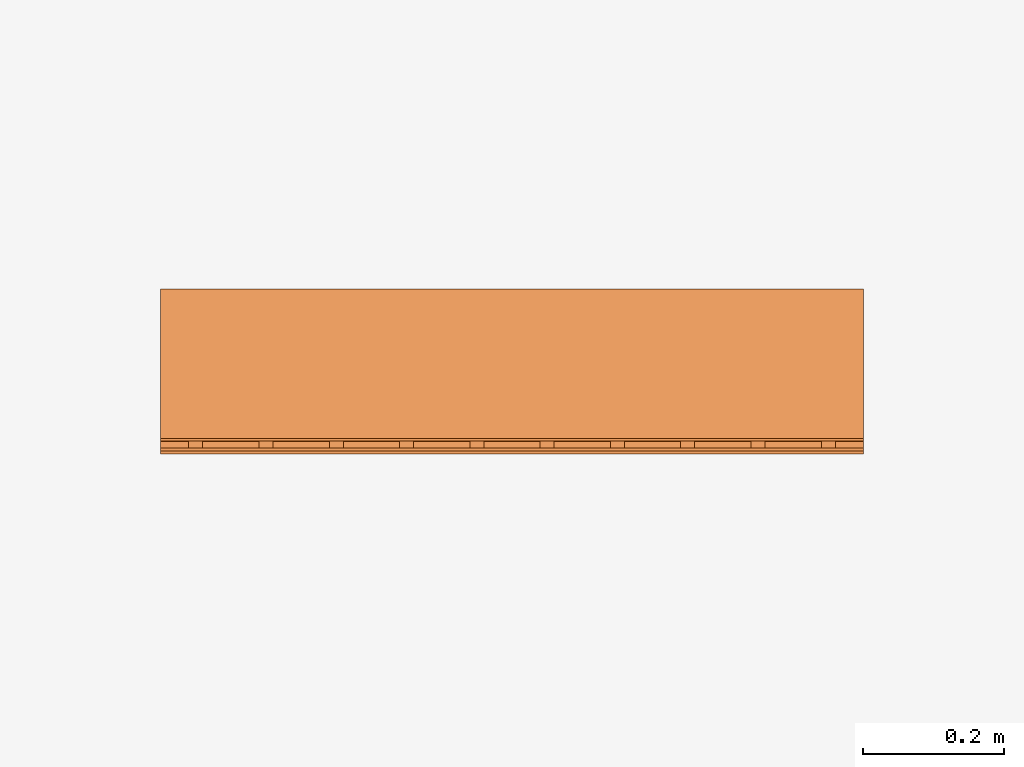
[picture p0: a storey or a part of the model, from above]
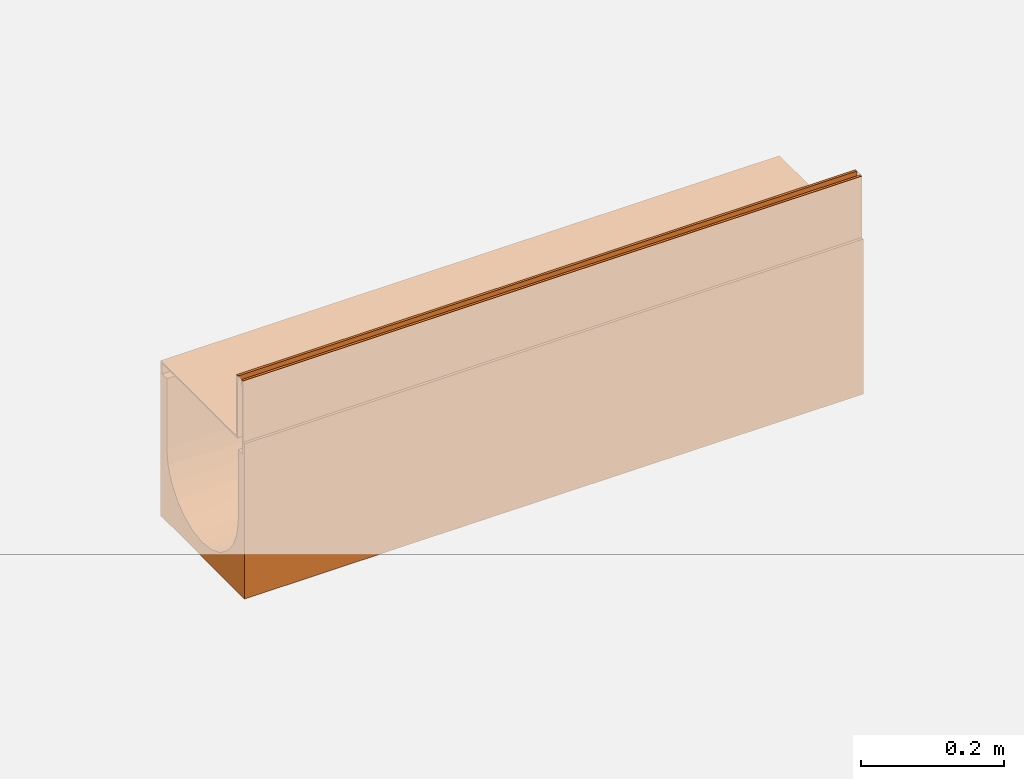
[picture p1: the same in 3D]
Properties of the parts of a building model (IFC2X3)

# File
Description: ViewDefinition [CoordinationView]
File name: 24210 - No 0.0 Constant Depth Channel - 1000mm LG - Invert Depth 240mm.ifc
Time: 2013-10-30T14:04:48
Written by: Autodesk Revit 2013
Made in: 20120221_2030(x64)

# IfcProject, Project Number
LongName: Project Name; Phase: Project Status

# IfcSite, Default
RefLatitude: 42, 21, 30, 344238; RefLongitude: -71, -3, -35, -194702; RefElevation: 0 mm

# IfcBuilding
Pset_BuildingCommon - NumberOfStoreys: 1
Other - Project Name: Project Name; Client Name: Owner; Project Status: Project Status; Project Number: Project Number; Project Address: ## Street City, State Zip; Project Issue Date: Issue Date

# IfcBuildingStorey, Level 1
LongName: Level 1; Elevation: 0 mm
Constraints - Elevation Base: 0; Elevation: 0 mm
Graphics - Line Pattern: Center; Symbol at End 1 Default: no; Symbol: M_Level Head - Circle: M_Level Head - Circle; Symbol at End 2 Default: yes; Line Weight: 1; Color: 0
Dimensions - Computation Height: 0 mm
Identity Data - Structural: no; Building Story: yes; Name: Level 1

# IfcBuildingElementProxy: 24210 - No 0.0 Constant Depth Channel - 1000mm LG - Invert Depth 240mm, Civil-Drainage-Channel-ACO-MultiDrain-M200DS-Brickslot-Channel-System:24210 - No 0.0 Constant Depth Channel - 1000mm LG - Invert Depth 240mm:24210 - No 0.0 Constant Depth Channel - 1000mm LG - Invert Depth 240mm:196059
In: Level 1
Material: Stainless Steel (F), Vienite® Synthetic Resin Concrete
Dimensions - FloorCut_Length: -1000 mm; Brickslot Access Unit Void Depth: 6000 mm; EndCap Position: 1000 mm; Volume: 19055290 mm3; Brickslot Access Unit Void Bottom Depth: 6105 mm; Brickslot Grating Void Depth: 0 mm; Length: 1000 mm; Brickslot Void Length: -1000 mm; Custom_Void_Length: 0 mm; InvDepth: 140 mm; FloorCut_Depth: 265 mm; FloorCut_Width: 235 mm; Length Drain: -1000 mm; EndCap_Height: 265 mm; FloorCut_HorPosition: 117.5 mm; Depth: 265 mm
Construction - 23219 - Universal Endcap (Male End): no; 408999_Load Class C250 & D400_Brickslot Grating_Stainless Steel_500mm Long: no; 409000_Load Class C250 & D400_Brickslot_Access Unit_Stainless Steel_500mm Long: no; 408998_Load Class C250 & D400_Brickslot Grating_Stainless Steel_1000mm Long: yes; 23219 - Universal Endcap (Female End): no; 23410_Sump Unit: no; Constant Depth Channel_1000: yes; Shallow Depth Channel with seal: no; Constant Depth Channel_500: no; Shallow Depth Channel: no
Constraints - Level: Level: Level 1; Moves With Nearby Elements: no
Phasing - Phase Created: New Construction
Pset_BuildingElementProxyCommon - Reference: 24210 - No 0.0 Constant Depth Channel - 1000mm LG - Invert Depth 240mm
Identity Data - Maintenance guidelines: http://www.aco.co.uk/download.php?id=173; Installation guidelines: http://www.aco.co.uk/download.php?id=173; Model: ACO MultiDrain MDS Brickslot - M200DS; e-mail Sales: customersupport@aco.co.uk; Assembly Description: Rain Water Drainage; Watermarked By: www.aco.co.uk; Product Page URL: http://www.aco.co.uk/product_detail.php?id=58; OmniClass Title: Rainwater Removal; Watermarked With: BIM Manager Premium Suite; OmniClass Number: 23.70.50.24; Price: POA - contact ACO; Cost: 0; e-mail Technical: technical@aco.co.uk; Fax: +44 (0)1462 815895; Type Comments: ACO MultiDrain M200DS 0.0 Constant Depth Channel 1000mm Long; URL: www.aco.co.uk; Product Code: 24210; Address: ACO Business Park, Hitchin Road, Shefford, Bedfordshire, United Kingdom SG17 5TE; Watermark 2: This file is water marked and users are prohibited to reproduce, adapt, distribute this information; Model Description: Channel drainage system; Assembly Code: D2040; Manufacturer: ACO Technologies plc - ACO Water Management Division; Telephone: +44 (0)1462 816666; Product brochure: http://www.aco.co.uk/download.php?id=173; Watermark 1: This file is the property of ACO Technologies PLC
Green Building Properties - Channel Recyclable: Fully recyclable; Channel Recycled Material Content: 20% minimum; Edge Rail Recycled Material Content: Between 40% - 90%; Edge Rail Recyclable: Fully recyclable
General - SerialNumber: 0; TagNumber: 0
Data - Invert Depth: 240mm; Concrete Surround Volume - Load Class B 125 - C 250 - Concrete Pavement: 0.17m³/m; Load Class: A 15 - D 400; Concrete Surround Volume - Load Class A 15 - Concrete Pavement: 0.11m³/m; Installation - Concrete Grade: Refer to brochure; Concrete Surround Volume - Load Class D 400 - Concrete Pavement: 0.24m³/m; Product Standard: BS EN 1433:2002, CE marked; ACO Hydraulic Design Software: http://www.acodesign.co.uk; Channel C.S.A: 0.035m²; Hydraulic Performance: http://www.aco.co.uk/download.php?id=173; Product Dimensions: 1000mm x 235mm x 265mm (LxWxH); Product Weight: 32.3 Kg
Materials and Finishes - Channel Material: Vienite® Synthetic Resin Concrete; Edge Rail Material: Stainless Steel Grade 304; Edge Rail Colour: Self; Channel Colour: Brown
Other - CreatedBy: www.aco.co.uk; Revision: 1
Model Properties - Brickslot Access Unit Product code 409000: Load Class C250/D400 - Brickslot Access Unit Stainless Steel - 500mm long x 105mm high - 10mm Slot - Intake area 10000mm²/m - 8.5 Kg; Brickslot Grating Product code 408999: Load Class C250/D400 - Brickslot Stainless Steel - 500mm long x 105mm high - 10mm Slot - Intake area 10000mm²/m - 4.8kg; End Cap Product code 23219: No 306 Universal End Cap - 235mm wide x 365mm long - Spigot Ø160mm x 75mm long - Silver - Polypropylene - 0.4kg; Brickslot Grating Product code 408998: Load Class C250/D400 - Brickslot Stainless Steel - 1000mm long x 105mm high - 10mm Slot - Intake area 10000mm²/m - 9.8kg

# IfcOpeningElement: Recess (2)
In: Level 1
Phasing - Phase Created: New Construction
Dimensions - Thickness: 400 mm; Volume: 9935835000 mm3; Perimeter: 20000 mm; Area: 25000000 mm2
Constraints - Height Offset From Level: 0 mm; Related to Mass: no; Room Bounding: yes; Level: Level: Level 1
Structural - Enable Analytical Model: no; Structural: no
Construction - Default Thickness: 400 mm; Function: 0
Materials and Finishes - Structural Material: Earth
Analytical Properties - Absorptance: 0.1; Heat Transfer Coefficient (U): 2.0925; Thermal Resistance (R): 0.477897; Thermal mass: 543920; Roughness: 1
Graphics - Coarse Scale Fill Color: 0

# IfcSlab: Floor:Generic Floor - 400mm, Floor:Generic Floor - 400mm:193825
In: Level 1
PredefinedType: FLOOR; Material: Earth 400 mm
Phasing - Phase Created: New Construction
Dimensions - Thickness: 400 mm; Volume: 9935835000 mm3; Perimeter: 20000 mm; Area: 25000000 mm2
Constraints - Height Offset From Level: 0 mm; Related to Mass: no; Room Bounding: yes; Level: Level: Level 1
Structural - Enable Analytical Model: no; Structural: no
Pset_SlabCommon - Reference: Generic Floor - 400mm; IsExternal: no; LoadBearing: yes
Construction - Default Thickness: 400 mm; Function: 0
Materials and Finishes - Structural Material: Earth
Analytical Properties - Absorptance: 0.1; Heat Transfer Coefficient (U): 2.0925; Thermal Resistance (R): 0.477897; Thermal mass: 543920; Roughness: 1
Graphics - Coarse Scale Fill Color: 0
